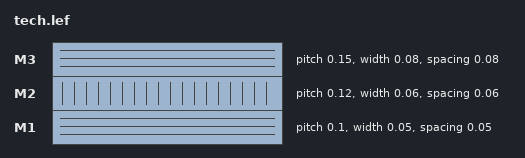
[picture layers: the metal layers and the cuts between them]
LAYER M1
  TYPE ROUTING ;
  DIRECTION HORIZONTAL ;
  PITCH 0.10 0.10 ;
  WIDTH 0.05 ;
  SPACING 0.05 ;
END M1

LAYER M2
  TYPE ROUTING ;
  DIRECTION VERTICAL ;
  PITCH 0.12 0.12 ;
  WIDTH 0.06 ;
  SPACING 0.06 ;
END M2

LAYER M3
  TYPE ROUTING ;
  DIRECTION HORIZONTAL ;
  PITCH 0.15 0.15 ;
  WIDTH 0.08 ;
  SPACING 0.08 ;
END M3
